VERSION 5.8 ;
BUSBITCHARS "[]" ;
DIVIDERCHAR "/" ;
UNITS
    DATABASE MICRONS 1000 ;
END UNITS

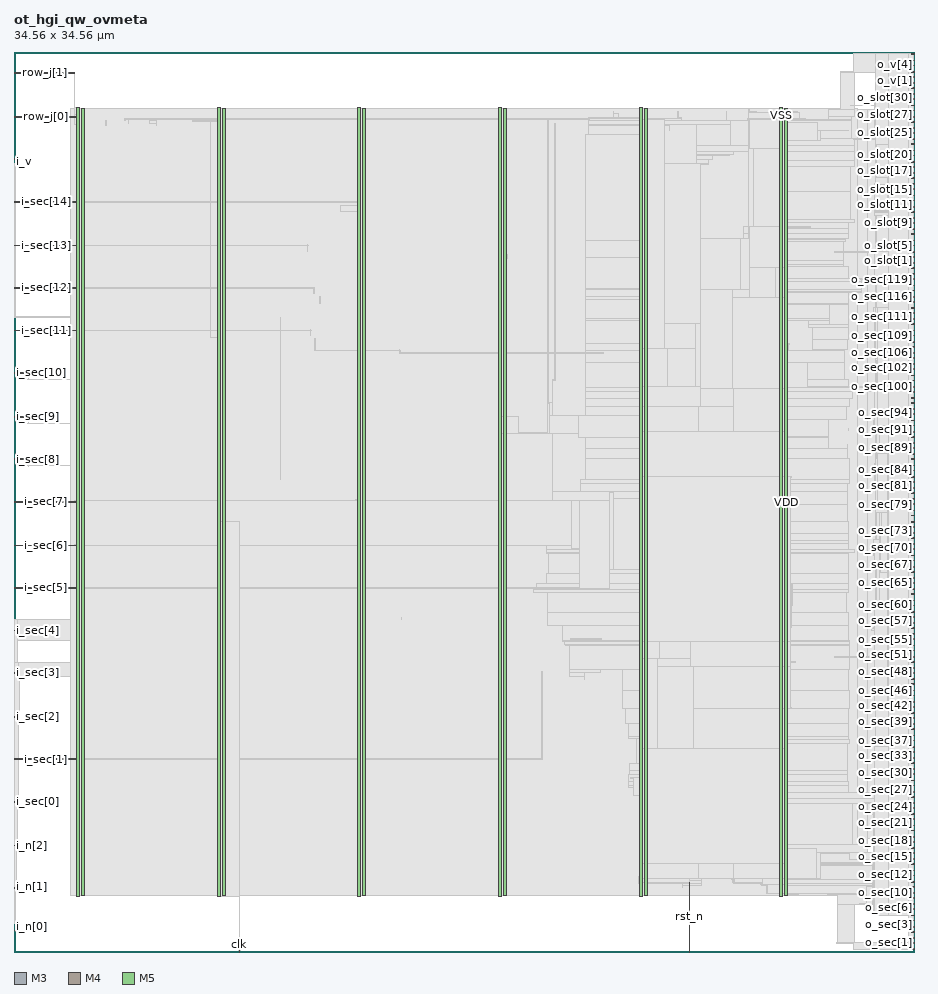
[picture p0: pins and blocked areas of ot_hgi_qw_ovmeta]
MACRO ot_hgi_qw_ovmeta
  FOREIGN ot_hgi_qw_ovmeta 0 0 ;
  CLASS BLOCK ;
  SIZE 34.56 BY 34.56 ;
  PIN clk
    DIRECTION INPUT ;
    USE SIGNAL ;
    PORT
      LAYER M3 ;
        RECT  8.64 0 8.658 0.038 ;
    END
    PORT
      LAYER M3 ;
        RECT  8.64 0.012 8.658 0.077 ;
    END
  END clk
  PIN i_n[0]
    DIRECTION INPUT ;
    USE SIGNAL ;
    PORT
      LAYER M4 ;
        RECT  0 0.816 0.084 0.84 ;
    END
    PORT
      LAYER M4 ;
        RECT  0.06 0.816 0.137 1.128 ;
    END
  END i_n[0]
  PIN i_n[1]
    DIRECTION INPUT ;
    USE SIGNAL ;
    PORT
      LAYER M4 ;
        RECT  0 2.448 0.084 2.472 ;
    END
    PORT
      LAYER M4 ;
        RECT  0.06 2.448 0.061 2.472 ;
    END
    PORT
      LAYER M4 ;
        RECT  0.061 2.448 0.173 2.568 ;
    END
  END i_n[1]
  PIN i_n[2]
    DIRECTION INPUT ;
    USE SIGNAL ;
    PORT
      LAYER M4 ;
        RECT  0 4.08 0.084 4.104 ;
    END
    PORT
      LAYER M4 ;
        RECT  0.06 4.08 0.137 4.104 ;
    END
  END i_n[2]
  PIN i_sec[0]
    DIRECTION INPUT ;
    USE SIGNAL ;
    PORT
      LAYER M4 ;
        RECT  0 5.76 0.084 5.784 ;
    END
    PORT
      LAYER M4 ;
        RECT  0.06 5.76 0.173 5.784 ;
    END
  END i_sec[0]
  PIN i_sec[10]
    DIRECTION INPUT ;
    USE SIGNAL ;
    PORT
      LAYER M4 ;
        RECT  0 22.224 0.084 22.248 ;
    END
    PORT
      LAYER M4 ;
        RECT  0.06 22.224 0.569 22.248 ;
    END
  END i_sec[10]
  PIN i_sec[11]
    DIRECTION INPUT ;
    USE SIGNAL ;
    PORT
      LAYER M4 ;
        RECT  0 23.856 0.084 23.88 ;
    END
    PORT
      LAYER M4 ;
        RECT  0.06 23.856 2.408 23.88 ;
    END
  END i_sec[11]
  PIN i_sec[12]
    DIRECTION INPUT ;
    USE SIGNAL ;
    PORT
      LAYER M4 ;
        RECT  0 25.488 0.084 25.512 ;
    END
    PORT
      LAYER M4 ;
        RECT  0.06 25.488 2.408 25.512 ;
    END
  END i_sec[12]
  PIN i_sec[13]
    DIRECTION INPUT ;
    USE SIGNAL ;
    PORT
      LAYER M4 ;
        RECT  0 27.12 0.084 27.144 ;
    END
    PORT
      LAYER M4 ;
        RECT  0.06 27.12 2.408 27.144 ;
    END
  END i_sec[13]
  PIN i_sec[14]
    DIRECTION INPUT ;
    USE SIGNAL ;
    PORT
      LAYER M4 ;
        RECT  0 28.8 0.084 28.824 ;
    END
    PORT
      LAYER M4 ;
        RECT  0.06 28.8 2.408 28.824 ;
    END
  END i_sec[14]
  PIN i_sec[1]
    DIRECTION INPUT ;
    USE SIGNAL ;
    PORT
      LAYER M4 ;
        RECT  0 7.392 0.084 7.416 ;
    END
    PORT
      LAYER M4 ;
        RECT  0.06 7.392 2.408 7.416 ;
    END
  END i_sec[1]
  PIN i_sec[2]
    DIRECTION INPUT ;
    USE SIGNAL ;
    PORT
      LAYER M4 ;
        RECT  0 9.024 0.084 9.048 ;
    END
    PORT
      LAYER M4 ;
        RECT  0.06 9.024 0.209 9.048 ;
    END
  END i_sec[2]
  PIN i_sec[3]
    DIRECTION INPUT ;
    USE SIGNAL ;
    PORT
      LAYER M4 ;
        RECT  0 10.704 0.084 10.728 ;
    END
    PORT
      LAYER M4 ;
        RECT  0.06 10.704 0.209 10.728 ;
    END
  END i_sec[3]
  PIN i_sec[4]
    DIRECTION INPUT ;
    USE SIGNAL ;
    PORT
      LAYER M4 ;
        RECT  0 12.336 0.084 12.36 ;
    END
    PORT
      LAYER M4 ;
        RECT  0.06 12.336 0.137 12.36 ;
    END
  END i_sec[4]
  PIN i_sec[5]
    DIRECTION INPUT ;
    USE SIGNAL ;
    PORT
      LAYER M4 ;
        RECT  0 13.968 0.084 13.992 ;
    END
    PORT
      LAYER M4 ;
        RECT  0.06 13.968 2.408 13.992 ;
    END
  END i_sec[5]
  PIN i_sec[6]
    DIRECTION INPUT ;
    USE SIGNAL ;
    PORT
      LAYER M4 ;
        RECT  0 15.6 0.084 15.624 ;
    END
    PORT
      LAYER M4 ;
        RECT  0.06 15.6 2.408 15.624 ;
    END
  END i_sec[6]
  PIN i_sec[7]
    DIRECTION INPUT ;
    USE SIGNAL ;
    PORT
      LAYER M4 ;
        RECT  0 17.28 0.084 17.304 ;
    END
    PORT
      LAYER M4 ;
        RECT  0.06 17.28 2.408 17.304 ;
    END
  END i_sec[7]
  PIN i_sec[8]
    DIRECTION INPUT ;
    USE SIGNAL ;
    PORT
      LAYER M4 ;
        RECT  0 18.912 0.084 18.936 ;
    END
    PORT
      LAYER M4 ;
        RECT  0.06 18.912 0.569 18.936 ;
    END
  END i_sec[8]
  PIN i_sec[9]
    DIRECTION INPUT ;
    USE SIGNAL ;
    PORT
      LAYER M4 ;
        RECT  0 20.544 0.084 20.568 ;
    END
    PORT
      LAYER M4 ;
        RECT  0.06 20.544 0.569 20.568 ;
    END
  END i_sec[9]
  PIN i_v
    DIRECTION INPUT ;
    USE SIGNAL ;
    PORT
      LAYER M4 ;
        RECT  0 30.432 0.084 30.456 ;
    END
    PORT
      LAYER M4 ;
        RECT  0.06 30.24 0.137 30.456 ;
    END
  END i_v
  PIN o_sec[0]
    DIRECTION OUTPUT ;
    USE SIGNAL ;
    PORT
      LAYER M4 ;
        RECT  34.476 0.096 34.56 0.12 ;
    END
  END o_sec[0]
  PIN o_sec[100]
    DIRECTION OUTPUT ;
    USE SIGNAL ;
    PORT
      LAYER M4 ;
        RECT  34.476 21.696 34.56 21.72 ;
    END
  END o_sec[100]
  PIN o_sec[101]
    DIRECTION OUTPUT ;
    USE SIGNAL ;
    PORT
      LAYER M4 ;
        RECT  34.476 21.936 34.56 21.96 ;
    END
  END o_sec[101]
  PIN o_sec[102]
    DIRECTION OUTPUT ;
    USE SIGNAL ;
    PORT
      LAYER M4 ;
        RECT  34.476 22.128 34.56 22.152 ;
    END
  END o_sec[102]
  PIN o_sec[103]
    DIRECTION OUTPUT ;
    USE SIGNAL ;
    PORT
      LAYER M4 ;
        RECT  34.476 22.368 34.56 22.392 ;
    END
  END o_sec[103]
  PIN o_sec[104]
    DIRECTION OUTPUT ;
    USE SIGNAL ;
    PORT
      LAYER M4 ;
        RECT  34.476 22.56 34.56 22.584 ;
    END
  END o_sec[104]
  PIN o_sec[105]
    DIRECTION OUTPUT ;
    USE SIGNAL ;
    PORT
      LAYER M4 ;
        RECT  34.476 22.8 34.56 22.824 ;
    END
  END o_sec[105]
  PIN o_sec[106]
    DIRECTION OUTPUT ;
    USE SIGNAL ;
    PORT
      LAYER M4 ;
        RECT  34.476 22.992 34.56 23.016 ;
    END
  END o_sec[106]
  PIN o_sec[107]
    DIRECTION OUTPUT ;
    USE SIGNAL ;
    PORT
      LAYER M4 ;
        RECT  34.476 23.232 34.56 23.256 ;
    END
  END o_sec[107]
  PIN o_sec[108]
    DIRECTION OUTPUT ;
    USE SIGNAL ;
    PORT
      LAYER M4 ;
        RECT  34.476 23.424 34.56 23.448 ;
    END
  END o_sec[108]
  PIN o_sec[109]
    DIRECTION OUTPUT ;
    USE SIGNAL ;
    PORT
      LAYER M4 ;
        RECT  34.476 23.664 34.56 23.688 ;
    END
  END o_sec[109]
  PIN o_sec[10]
    DIRECTION OUTPUT ;
    USE SIGNAL ;
    PORT
      LAYER M4 ;
        RECT  34.476 2.256 34.56 2.28 ;
    END
  END o_sec[10]
  PIN o_sec[110]
    DIRECTION OUTPUT ;
    USE SIGNAL ;
    PORT
      LAYER M4 ;
        RECT  34.476 23.856 34.56 23.88 ;
    END
  END o_sec[110]
  PIN o_sec[111]
    DIRECTION OUTPUT ;
    USE SIGNAL ;
    PORT
      LAYER M4 ;
        RECT  34.476 24.096 34.56 24.12 ;
    END
  END o_sec[111]
  PIN o_sec[112]
    DIRECTION OUTPUT ;
    USE SIGNAL ;
    PORT
      LAYER M4 ;
        RECT  34.476 24.288 34.56 24.312 ;
    END
  END o_sec[112]
  PIN o_sec[113]
    DIRECTION OUTPUT ;
    USE SIGNAL ;
    PORT
      LAYER M4 ;
        RECT  34.476 24.528 34.56 24.552 ;
    END
  END o_sec[113]
  PIN o_sec[114]
    DIRECTION OUTPUT ;
    USE SIGNAL ;
    PORT
      LAYER M4 ;
        RECT  34.476 24.72 34.56 24.744 ;
    END
  END o_sec[114]
  PIN o_sec[115]
    DIRECTION OUTPUT ;
    USE SIGNAL ;
    PORT
      LAYER M4 ;
        RECT  34.476 24.96 34.56 24.984 ;
    END
  END o_sec[115]
  PIN o_sec[116]
    DIRECTION OUTPUT ;
    USE SIGNAL ;
    PORT
      LAYER M4 ;
        RECT  34.476 25.152 34.56 25.176 ;
    END
  END o_sec[116]
  PIN o_sec[117]
    DIRECTION OUTPUT ;
    USE SIGNAL ;
    PORT
      LAYER M4 ;
        RECT  34.476 25.392 34.56 25.416 ;
    END
  END o_sec[117]
  PIN o_sec[118]
    DIRECTION OUTPUT ;
    USE SIGNAL ;
    PORT
      LAYER M4 ;
        RECT  34.476 25.584 34.56 25.608 ;
    END
  END o_sec[118]
  PIN o_sec[119]
    DIRECTION OUTPUT ;
    USE SIGNAL ;
    PORT
      LAYER M4 ;
        RECT  34.476 25.824 34.56 25.848 ;
    END
  END o_sec[119]
  PIN o_sec[11]
    DIRECTION OUTPUT ;
    USE SIGNAL ;
    PORT
      LAYER M4 ;
        RECT  34.476 2.496 34.56 2.52 ;
    END
  END o_sec[11]
  PIN o_sec[12]
    DIRECTION OUTPUT ;
    USE SIGNAL ;
    PORT
      LAYER M4 ;
        RECT  34.476 2.688 34.56 2.712 ;
    END
  END o_sec[12]
  PIN o_sec[13]
    DIRECTION OUTPUT ;
    USE SIGNAL ;
    PORT
      LAYER M4 ;
        RECT  34.476 2.928 34.56 2.952 ;
    END
  END o_sec[13]
  PIN o_sec[14]
    DIRECTION OUTPUT ;
    USE SIGNAL ;
    PORT
      LAYER M4 ;
        RECT  34.476 3.12 34.56 3.144 ;
    END
  END o_sec[14]
  PIN o_sec[15]
    DIRECTION OUTPUT ;
    USE SIGNAL ;
    PORT
      LAYER M4 ;
        RECT  34.476 3.36 34.56 3.384 ;
    END
  END o_sec[15]
  PIN o_sec[16]
    DIRECTION OUTPUT ;
    USE SIGNAL ;
    PORT
      LAYER M4 ;
        RECT  34.476 3.552 34.56 3.576 ;
    END
  END o_sec[16]
  PIN o_sec[17]
    DIRECTION OUTPUT ;
    USE SIGNAL ;
    PORT
      LAYER M4 ;
        RECT  34.476 3.792 34.56 3.816 ;
    END
  END o_sec[17]
  PIN o_sec[18]
    DIRECTION OUTPUT ;
    USE SIGNAL ;
    PORT
      LAYER M4 ;
        RECT  34.476 3.984 34.56 4.008 ;
    END
  END o_sec[18]
  PIN o_sec[19]
    DIRECTION OUTPUT ;
    USE SIGNAL ;
    PORT
      LAYER M4 ;
        RECT  34.476 4.224 34.56 4.248 ;
    END
  END o_sec[19]
  PIN o_sec[1]
    DIRECTION OUTPUT ;
    USE SIGNAL ;
    PORT
      LAYER M4 ;
        RECT  34.476 0.336 34.56 0.36 ;
    END
  END o_sec[1]
  PIN o_sec[20]
    DIRECTION OUTPUT ;
    USE SIGNAL ;
    PORT
      LAYER M4 ;
        RECT  34.476 4.416 34.56 4.44 ;
    END
  END o_sec[20]
  PIN o_sec[21]
    DIRECTION OUTPUT ;
    USE SIGNAL ;
    PORT
      LAYER M4 ;
        RECT  34.476 4.656 34.56 4.68 ;
    END
  END o_sec[21]
  PIN o_sec[22]
    DIRECTION OUTPUT ;
    USE SIGNAL ;
    PORT
      LAYER M4 ;
        RECT  34.476 4.848 34.56 4.872 ;
    END
  END o_sec[22]
  PIN o_sec[23]
    DIRECTION OUTPUT ;
    USE SIGNAL ;
    PORT
      LAYER M4 ;
        RECT  34.476 5.088 34.56 5.112 ;
    END
  END o_sec[23]
  PIN o_sec[24]
    DIRECTION OUTPUT ;
    USE SIGNAL ;
    PORT
      LAYER M4 ;
        RECT  34.476 5.28 34.56 5.304 ;
    END
  END o_sec[24]
  PIN o_sec[25]
    DIRECTION OUTPUT ;
    USE SIGNAL ;
    PORT
      LAYER M4 ;
        RECT  34.476 5.52 34.56 5.544 ;
    END
  END o_sec[25]
  PIN o_sec[26]
    DIRECTION OUTPUT ;
    USE SIGNAL ;
    PORT
      LAYER M4 ;
        RECT  34.476 5.712 34.56 5.736 ;
    END
  END o_sec[26]
  PIN o_sec[27]
    DIRECTION OUTPUT ;
    USE SIGNAL ;
    PORT
      LAYER M4 ;
        RECT  34.476 5.952 34.56 5.976 ;
    END
  END o_sec[27]
  PIN o_sec[28]
    DIRECTION OUTPUT ;
    USE SIGNAL ;
    PORT
      LAYER M4 ;
        RECT  34.476 6.144 34.56 6.168 ;
    END
  END o_sec[28]
  PIN o_sec[29]
    DIRECTION OUTPUT ;
    USE SIGNAL ;
    PORT
      LAYER M4 ;
        RECT  34.476 6.384 34.56 6.408 ;
    END
  END o_sec[29]
  PIN o_sec[2]
    DIRECTION OUTPUT ;
    USE SIGNAL ;
    PORT
      LAYER M4 ;
        RECT  34.476 0.528 34.56 0.552 ;
    END
  END o_sec[2]
  PIN o_sec[30]
    DIRECTION OUTPUT ;
    USE SIGNAL ;
    PORT
      LAYER M4 ;
        RECT  34.476 6.576 34.56 6.6 ;
    END
  END o_sec[30]
  PIN o_sec[31]
    DIRECTION OUTPUT ;
    USE SIGNAL ;
    PORT
      LAYER M4 ;
        RECT  34.476 6.816 34.56 6.84 ;
    END
  END o_sec[31]
  PIN o_sec[32]
    DIRECTION OUTPUT ;
    USE SIGNAL ;
    PORT
      LAYER M4 ;
        RECT  34.476 7.008 34.56 7.032 ;
    END
  END o_sec[32]
  PIN o_sec[33]
    DIRECTION OUTPUT ;
    USE SIGNAL ;
    PORT
      LAYER M4 ;
        RECT  34.476 7.248 34.56 7.272 ;
    END
  END o_sec[33]
  PIN o_sec[34]
    DIRECTION OUTPUT ;
    USE SIGNAL ;
    PORT
      LAYER M4 ;
        RECT  34.476 7.44 34.56 7.464 ;
    END
  END o_sec[34]
  PIN o_sec[35]
    DIRECTION OUTPUT ;
    USE SIGNAL ;
    PORT
      LAYER M4 ;
        RECT  34.476 7.68 34.56 7.704 ;
    END
  END o_sec[35]
  PIN o_sec[36]
    DIRECTION OUTPUT ;
    USE SIGNAL ;
    PORT
      LAYER M4 ;
        RECT  34.476 7.872 34.56 7.896 ;
    END
  END o_sec[36]
  PIN o_sec[37]
    DIRECTION OUTPUT ;
    USE SIGNAL ;
    PORT
      LAYER M4 ;
        RECT  34.476 8.112 34.56 8.136 ;
    END
  END o_sec[37]
  PIN o_sec[38]
    DIRECTION OUTPUT ;
    USE SIGNAL ;
    PORT
      LAYER M4 ;
        RECT  34.476 8.304 34.56 8.328 ;
    END
  END o_sec[38]
  PIN o_sec[39]
    DIRECTION OUTPUT ;
    USE SIGNAL ;
    PORT
      LAYER M4 ;
        RECT  34.476 8.544 34.56 8.568 ;
    END
  END o_sec[39]
  PIN o_sec[3]
    DIRECTION OUTPUT ;
    USE SIGNAL ;
    PORT
      LAYER M4 ;
        RECT  34.476 0.768 34.56 0.792 ;
    END
  END o_sec[3]
  PIN o_sec[40]
    DIRECTION OUTPUT ;
    USE SIGNAL ;
    PORT
      LAYER M4 ;
        RECT  34.476 8.736 34.56 8.76 ;
    END
  END o_sec[40]
  PIN o_sec[41]
    DIRECTION OUTPUT ;
    USE SIGNAL ;
    PORT
      LAYER M4 ;
        RECT  34.476 8.976 34.56 9 ;
    END
  END o_sec[41]
  PIN o_sec[42]
    DIRECTION OUTPUT ;
    USE SIGNAL ;
    PORT
      LAYER M4 ;
        RECT  34.476 9.168 34.56 9.192 ;
    END
  END o_sec[42]
  PIN o_sec[43]
    DIRECTION OUTPUT ;
    USE SIGNAL ;
    PORT
      LAYER M4 ;
        RECT  34.476 9.408 34.56 9.432 ;
    END
  END o_sec[43]
  PIN o_sec[44]
    DIRECTION OUTPUT ;
    USE SIGNAL ;
    PORT
      LAYER M4 ;
        RECT  34.476 9.6 34.56 9.624 ;
    END
  END o_sec[44]
  PIN o_sec[45]
    DIRECTION OUTPUT ;
    USE SIGNAL ;
    PORT
      LAYER M4 ;
        RECT  34.476 9.84 34.56 9.864 ;
    END
  END o_sec[45]
  PIN o_sec[46]
    DIRECTION OUTPUT ;
    USE SIGNAL ;
    PORT
      LAYER M4 ;
        RECT  34.476 10.032 34.56 10.056 ;
    END
  END o_sec[46]
  PIN o_sec[47]
    DIRECTION OUTPUT ;
    USE SIGNAL ;
    PORT
      LAYER M4 ;
        RECT  34.476 10.272 34.56 10.296 ;
    END
  END o_sec[47]
  PIN o_sec[48]
    DIRECTION OUTPUT ;
    USE SIGNAL ;
    PORT
      LAYER M4 ;
        RECT  34.476 10.464 34.56 10.488 ;
    END
  END o_sec[48]
  PIN o_sec[49]
    DIRECTION OUTPUT ;
    USE SIGNAL ;
    PORT
      LAYER M4 ;
        RECT  34.476 10.704 34.56 10.728 ;
    END
  END o_sec[49]
  PIN o_sec[4]
    DIRECTION OUTPUT ;
    USE SIGNAL ;
    PORT
      LAYER M4 ;
        RECT  34.476 0.96 34.56 0.984 ;
    END
  END o_sec[4]
  PIN o_sec[50]
    DIRECTION OUTPUT ;
    USE SIGNAL ;
    PORT
      LAYER M4 ;
        RECT  34.476 10.896 34.56 10.92 ;
    END
  END o_sec[50]
  PIN o_sec[51]
    DIRECTION OUTPUT ;
    USE SIGNAL ;
    PORT
      LAYER M4 ;
        RECT  34.476 11.136 34.56 11.16 ;
    END
  END o_sec[51]
  PIN o_sec[52]
    DIRECTION OUTPUT ;
    USE SIGNAL ;
    PORT
      LAYER M4 ;
        RECT  34.476 11.328 34.56 11.352 ;
    END
  END o_sec[52]
  PIN o_sec[53]
    DIRECTION OUTPUT ;
    USE SIGNAL ;
    PORT
      LAYER M4 ;
        RECT  34.476 11.568 34.56 11.592 ;
    END
  END o_sec[53]
  PIN o_sec[54]
    DIRECTION OUTPUT ;
    USE SIGNAL ;
    PORT
      LAYER M4 ;
        RECT  34.476 11.76 34.56 11.784 ;
    END
  END o_sec[54]
  PIN o_sec[55]
    DIRECTION OUTPUT ;
    USE SIGNAL ;
    PORT
      LAYER M4 ;
        RECT  34.476 12 34.56 12.024 ;
    END
  END o_sec[55]
  PIN o_sec[56]
    DIRECTION OUTPUT ;
    USE SIGNAL ;
    PORT
      LAYER M4 ;
        RECT  34.476 12.192 34.56 12.216 ;
    END
  END o_sec[56]
  PIN o_sec[57]
    DIRECTION OUTPUT ;
    USE SIGNAL ;
    PORT
      LAYER M4 ;
        RECT  34.476 12.432 34.56 12.456 ;
    END
  END o_sec[57]
  PIN o_sec[58]
    DIRECTION OUTPUT ;
    USE SIGNAL ;
    PORT
      LAYER M4 ;
        RECT  34.476 12.624 34.56 12.648 ;
    END
  END o_sec[58]
  PIN o_sec[59]
    DIRECTION OUTPUT ;
    USE SIGNAL ;
    PORT
      LAYER M4 ;
        RECT  34.476 12.864 34.56 12.888 ;
    END
  END o_sec[59]
  PIN o_sec[5]
    DIRECTION OUTPUT ;
    USE SIGNAL ;
    PORT
      LAYER M4 ;
        RECT  34.476 1.2 34.56 1.224 ;
    END
  END o_sec[5]
  PIN o_sec[60]
    DIRECTION OUTPUT ;
    USE SIGNAL ;
    PORT
      LAYER M4 ;
        RECT  34.476 13.056 34.56 13.08 ;
    END
  END o_sec[60]
  PIN o_sec[61]
    DIRECTION OUTPUT ;
    USE SIGNAL ;
    PORT
      LAYER M4 ;
        RECT  34.476 13.296 34.56 13.32 ;
    END
  END o_sec[61]
  PIN o_sec[62]
    DIRECTION OUTPUT ;
    USE SIGNAL ;
    PORT
      LAYER M4 ;
        RECT  34.476 13.488 34.56 13.512 ;
    END
  END o_sec[62]
  PIN o_sec[63]
    DIRECTION OUTPUT ;
    USE SIGNAL ;
    PORT
      LAYER M4 ;
        RECT  34.476 13.728 34.56 13.752 ;
    END
  END o_sec[63]
  PIN o_sec[64]
    DIRECTION OUTPUT ;
    USE SIGNAL ;
    PORT
      LAYER M4 ;
        RECT  34.476 13.92 34.56 13.944 ;
    END
  END o_sec[64]
  PIN o_sec[65]
    DIRECTION OUTPUT ;
    USE SIGNAL ;
    PORT
      LAYER M4 ;
        RECT  34.476 14.16 34.56 14.184 ;
    END
  END o_sec[65]
  PIN o_sec[66]
    DIRECTION OUTPUT ;
    USE SIGNAL ;
    PORT
      LAYER M4 ;
        RECT  34.476 14.352 34.56 14.376 ;
    END
  END o_sec[66]
  PIN o_sec[67]
    DIRECTION OUTPUT ;
    USE SIGNAL ;
    PORT
      LAYER M4 ;
        RECT  34.476 14.592 34.56 14.616 ;
    END
  END o_sec[67]
  PIN o_sec[68]
    DIRECTION OUTPUT ;
    USE SIGNAL ;
    PORT
      LAYER M4 ;
        RECT  34.476 14.784 34.56 14.808 ;
    END
  END o_sec[68]
  PIN o_sec[69]
    DIRECTION OUTPUT ;
    USE SIGNAL ;
    PORT
      LAYER M4 ;
        RECT  34.476 15.024 34.56 15.048 ;
    END
  END o_sec[69]
  PIN o_sec[6]
    DIRECTION OUTPUT ;
    USE SIGNAL ;
    PORT
      LAYER M4 ;
        RECT  34.476 1.392 34.56 1.416 ;
    END
  END o_sec[6]
  PIN o_sec[70]
    DIRECTION OUTPUT ;
    USE SIGNAL ;
    PORT
      LAYER M4 ;
        RECT  34.476 15.216 34.56 15.24 ;
    END
  END o_sec[70]
  PIN o_sec[71]
    DIRECTION OUTPUT ;
    USE SIGNAL ;
    PORT
      LAYER M4 ;
        RECT  34.476 15.456 34.56 15.48 ;
    END
  END o_sec[71]
  PIN o_sec[72]
    DIRECTION OUTPUT ;
    USE SIGNAL ;
    PORT
      LAYER M4 ;
        RECT  34.476 15.648 34.56 15.672 ;
    END
  END o_sec[72]
  PIN o_sec[73]
    DIRECTION OUTPUT ;
    USE SIGNAL ;
    PORT
      LAYER M4 ;
        RECT  34.476 15.888 34.56 15.912 ;
    END
  END o_sec[73]
  PIN o_sec[74]
    DIRECTION OUTPUT ;
    USE SIGNAL ;
    PORT
      LAYER M4 ;
        RECT  34.476 16.08 34.56 16.104 ;
    END
  END o_sec[74]
  PIN o_sec[75]
    DIRECTION OUTPUT ;
    USE SIGNAL ;
    PORT
      LAYER M4 ;
        RECT  34.476 16.32 34.56 16.344 ;
    END
  END o_sec[75]
  PIN o_sec[76]
    DIRECTION OUTPUT ;
    USE SIGNAL ;
    PORT
      LAYER M4 ;
        RECT  34.476 16.512 34.56 16.536 ;
    END
  END o_sec[76]
  PIN o_sec[77]
    DIRECTION OUTPUT ;
    USE SIGNAL ;
    PORT
      LAYER M4 ;
        RECT  34.476 16.752 34.56 16.776 ;
    END
  END o_sec[77]
  PIN o_sec[78]
    DIRECTION OUTPUT ;
    USE SIGNAL ;
    PORT
      LAYER M4 ;
        RECT  34.476 16.944 34.56 16.968 ;
    END
  END o_sec[78]
  PIN o_sec[79]
    DIRECTION OUTPUT ;
    USE SIGNAL ;
    PORT
      LAYER M4 ;
        RECT  34.476 17.184 34.56 17.208 ;
    END
  END o_sec[79]
  PIN o_sec[7]
    DIRECTION OUTPUT ;
    USE SIGNAL ;
    PORT
      LAYER M4 ;
        RECT  34.476 1.632 34.56 1.656 ;
    END
  END o_sec[7]
  PIN o_sec[80]
    DIRECTION OUTPUT ;
    USE SIGNAL ;
    PORT
      LAYER M4 ;
        RECT  34.476 17.376 34.56 17.4 ;
    END
  END o_sec[80]
  PIN o_sec[81]
    DIRECTION OUTPUT ;
    USE SIGNAL ;
    PORT
      LAYER M4 ;
        RECT  34.476 17.616 34.56 17.64 ;
    END
  END o_sec[81]
  PIN o_sec[82]
    DIRECTION OUTPUT ;
    USE SIGNAL ;
    PORT
      LAYER M4 ;
        RECT  34.476 17.808 34.56 17.832 ;
    END
  END o_sec[82]
  PIN o_sec[83]
    DIRECTION OUTPUT ;
    USE SIGNAL ;
    PORT
      LAYER M4 ;
        RECT  34.476 18.048 34.56 18.072 ;
    END
  END o_sec[83]
  PIN o_sec[84]
    DIRECTION OUTPUT ;
    USE SIGNAL ;
    PORT
      LAYER M4 ;
        RECT  34.476 18.24 34.56 18.264 ;
    END
  END o_sec[84]
  PIN o_sec[85]
    DIRECTION OUTPUT ;
    USE SIGNAL ;
    PORT
      LAYER M4 ;
        RECT  34.476 18.48 34.56 18.504 ;
    END
  END o_sec[85]
  PIN o_sec[86]
    DIRECTION OUTPUT ;
    USE SIGNAL ;
    PORT
      LAYER M4 ;
        RECT  34.476 18.672 34.56 18.696 ;
    END
  END o_sec[86]
  PIN o_sec[87]
    DIRECTION OUTPUT ;
    USE SIGNAL ;
    PORT
      LAYER M4 ;
        RECT  34.476 18.912 34.56 18.936 ;
    END
  END o_sec[87]
  PIN o_sec[88]
    DIRECTION OUTPUT ;
    USE SIGNAL ;
    PORT
      LAYER M4 ;
        RECT  34.476 19.104 34.56 19.128 ;
    END
  END o_sec[88]
  PIN o_sec[89]
    DIRECTION OUTPUT ;
    USE SIGNAL ;
    PORT
      LAYER M4 ;
        RECT  34.476 19.344 34.56 19.368 ;
    END
  END o_sec[89]
  PIN o_sec[8]
    DIRECTION OUTPUT ;
    USE SIGNAL ;
    PORT
      LAYER M4 ;
        RECT  34.476 1.824 34.56 1.848 ;
    END
  END o_sec[8]
  PIN o_sec[90]
    DIRECTION OUTPUT ;
    USE SIGNAL ;
    PORT
      LAYER M4 ;
        RECT  34.476 19.536 34.56 19.56 ;
    END
  END o_sec[90]
  PIN o_sec[91]
    DIRECTION OUTPUT ;
    USE SIGNAL ;
    PORT
      LAYER M4 ;
        RECT  34.476 19.776 34.56 19.8 ;
    END
  END o_sec[91]
  PIN o_sec[92]
    DIRECTION OUTPUT ;
    USE SIGNAL ;
    PORT
      LAYER M4 ;
        RECT  34.476 19.968 34.56 19.992 ;
    END
  END o_sec[92]
  PIN o_sec[93]
    DIRECTION OUTPUT ;
    USE SIGNAL ;
    PORT
      LAYER M4 ;
        RECT  34.476 20.208 34.56 20.232 ;
    END
  END o_sec[93]
  PIN o_sec[94]
    DIRECTION OUTPUT ;
    USE SIGNAL ;
    PORT
      LAYER M4 ;
        RECT  34.476 20.4 34.56 20.424 ;
    END
  END o_sec[94]
  PIN o_sec[95]
    DIRECTION OUTPUT ;
    USE SIGNAL ;
    PORT
      LAYER M4 ;
        RECT  34.476 20.64 34.56 20.664 ;
    END
  END o_sec[95]
  PIN o_sec[96]
    DIRECTION OUTPUT ;
    USE SIGNAL ;
    PORT
      LAYER M4 ;
        RECT  34.476 20.832 34.56 20.856 ;
    END
  END o_sec[96]
  PIN o_sec[97]
    DIRECTION OUTPUT ;
    USE SIGNAL ;
    PORT
      LAYER M4 ;
        RECT  34.476 21.072 34.56 21.096 ;
    END
  END o_sec[97]
  PIN o_sec[98]
    DIRECTION OUTPUT ;
    USE SIGNAL ;
    PORT
      LAYER M4 ;
        RECT  34.476 21.264 34.56 21.288 ;
    END
  END o_sec[98]
  PIN o_sec[99]
    DIRECTION OUTPUT ;
    USE SIGNAL ;
    PORT
      LAYER M4 ;
        RECT  34.476 21.504 34.56 21.528 ;
    END
  END o_sec[99]
  PIN o_sec[9]
    DIRECTION OUTPUT ;
    USE SIGNAL ;
    PORT
      LAYER M4 ;
        RECT  34.476 2.064 34.56 2.088 ;
    END
  END o_sec[9]
  PIN o_slot[0]
    DIRECTION OUTPUT ;
    USE SIGNAL ;
    PORT
      LAYER M4 ;
        RECT  34.476 26.016 34.56 26.04 ;
    END
  END o_slot[0]
  PIN o_slot[10]
    DIRECTION OUTPUT ;
    USE SIGNAL ;
    PORT
      LAYER M4 ;
        RECT  34.476 28.176 34.56 28.2 ;
    END
  END o_slot[10]
  PIN o_slot[11]
    DIRECTION OUTPUT ;
    USE SIGNAL ;
    PORT
      LAYER M4 ;
        RECT  34.476 28.416 34.56 28.44 ;
    END
  END o_slot[11]
  PIN o_slot[12]
    DIRECTION OUTPUT ;
    USE SIGNAL ;
    PORT
      LAYER M4 ;
        RECT  34.476 28.608 34.56 28.632 ;
    END
  END o_slot[12]
  PIN o_slot[13]
    DIRECTION OUTPUT ;
    USE SIGNAL ;
    PORT
      LAYER M4 ;
        RECT  34.476 28.848 34.56 28.872 ;
    END
  END o_slot[13]
  PIN o_slot[14]
    DIRECTION OUTPUT ;
    USE SIGNAL ;
    PORT
      LAYER M4 ;
        RECT  34.476 29.04 34.56 29.064 ;
    END
  END o_slot[14]
  PIN o_slot[15]
    DIRECTION OUTPUT ;
    USE SIGNAL ;
    PORT
      LAYER M4 ;
        RECT  34.476 29.28 34.56 29.304 ;
    END
  END o_slot[15]
  PIN o_slot[16]
    DIRECTION OUTPUT ;
    USE SIGNAL ;
    PORT
      LAYER M4 ;
        RECT  34.476 29.472 34.56 29.496 ;
    END
  END o_slot[16]
  PIN o_slot[17]
    DIRECTION OUTPUT ;
    USE SIGNAL ;
    PORT
      LAYER M4 ;
        RECT  34.476 29.712 34.56 29.736 ;
    END
  END o_slot[17]
  PIN o_slot[18]
    DIRECTION OUTPUT ;
    USE SIGNAL ;
    PORT
      LAYER M4 ;
        RECT  34.476 29.904 34.56 29.928 ;
    END
  END o_slot[18]
  PIN o_slot[19]
    DIRECTION OUTPUT ;
    USE SIGNAL ;
    PORT
      LAYER M4 ;
        RECT  34.476 30.144 34.56 30.168 ;
    END
  END o_slot[19]
  PIN o_slot[1]
    DIRECTION OUTPUT ;
    USE SIGNAL ;
    PORT
      LAYER M4 ;
        RECT  34.476 26.256 34.56 26.28 ;
    END
  END o_slot[1]
  PIN o_slot[20]
    DIRECTION OUTPUT ;
    USE SIGNAL ;
    PORT
      LAYER M4 ;
        RECT  34.476 30.336 34.56 30.36 ;
    END
  END o_slot[20]
  PIN o_slot[21]
    DIRECTION OUTPUT ;
    USE SIGNAL ;
    PORT
      LAYER M4 ;
        RECT  34.476 30.576 34.56 30.6 ;
    END
  END o_slot[21]
  PIN o_slot[22]
    DIRECTION OUTPUT ;
    USE SIGNAL ;
    PORT
      LAYER M4 ;
        RECT  34.476 30.768 34.56 30.792 ;
    END
  END o_slot[22]
  PIN o_slot[23]
    DIRECTION OUTPUT ;
    USE SIGNAL ;
    PORT
      LAYER M4 ;
        RECT  34.476 31.008 34.56 31.032 ;
    END
  END o_slot[23]
  PIN o_slot[24]
    DIRECTION OUTPUT ;
    USE SIGNAL ;
    PORT
      LAYER M4 ;
        RECT  34.476 31.2 34.56 31.224 ;
    END
  END o_slot[24]
  PIN o_slot[25]
    DIRECTION OUTPUT ;
    USE SIGNAL ;
    PORT
      LAYER M4 ;
        RECT  34.476 31.44 34.56 31.464 ;
    END
  END o_slot[25]
  PIN o_slot[26]
    DIRECTION OUTPUT ;
    USE SIGNAL ;
    PORT
      LAYER M4 ;
        RECT  34.476 31.632 34.56 31.656 ;
    END
  END o_slot[26]
  PIN o_slot[27]
    DIRECTION OUTPUT ;
    USE SIGNAL ;
    PORT
      LAYER M4 ;
        RECT  34.476 31.872 34.56 31.896 ;
    END
  END o_slot[27]
  PIN o_slot[28]
    DIRECTION OUTPUT ;
    USE SIGNAL ;
    PORT
      LAYER M4 ;
        RECT  34.476 32.064 34.56 32.088 ;
    END
  END o_slot[28]
  PIN o_slot[29]
    DIRECTION OUTPUT ;
    USE SIGNAL ;
    PORT
      LAYER M4 ;
        RECT  34.476 32.304 34.56 32.328 ;
    END
  END o_slot[29]
  PIN o_slot[2]
    DIRECTION OUTPUT ;
    USE SIGNAL ;
    PORT
      LAYER M4 ;
        RECT  34.476 26.448 34.56 26.472 ;
    END
  END o_slot[2]
  PIN o_slot[30]
    DIRECTION OUTPUT ;
    USE SIGNAL ;
    PORT
      LAYER M4 ;
        RECT  34.476 32.496 34.56 32.52 ;
    END
  END o_slot[30]
  PIN o_slot[31]
    DIRECTION OUTPUT ;
    USE SIGNAL ;
    PORT
      LAYER M4 ;
        RECT  34.476 32.736 34.56 32.76 ;
    END
  END o_slot[31]
  PIN o_slot[3]
    DIRECTION OUTPUT ;
    USE SIGNAL ;
    PORT
      LAYER M4 ;
        RECT  34.476 26.688 34.56 26.712 ;
    END
  END o_slot[3]
  PIN o_slot[4]
    DIRECTION OUTPUT ;
    USE SIGNAL ;
    PORT
      LAYER M4 ;
        RECT  34.476 26.88 34.56 26.904 ;
    END
  END o_slot[4]
  PIN o_slot[5]
    DIRECTION OUTPUT ;
    USE SIGNAL ;
    PORT
      LAYER M4 ;
        RECT  34.476 27.12 34.56 27.144 ;
    END
  END o_slot[5]
  PIN o_slot[6]
    DIRECTION OUTPUT ;
    USE SIGNAL ;
    PORT
      LAYER M4 ;
        RECT  34.476 27.312 34.56 27.336 ;
    END
  END o_slot[6]
  PIN o_slot[7]
    DIRECTION OUTPUT ;
    USE SIGNAL ;
    PORT
      LAYER M4 ;
        RECT  34.476 27.552 34.56 27.576 ;
    END
  END o_slot[7]
  PIN o_slot[8]
    DIRECTION OUTPUT ;
    USE SIGNAL ;
    PORT
      LAYER M4 ;
        RECT  34.476 27.744 34.56 27.768 ;
    END
  END o_slot[8]
  PIN o_slot[9]
    DIRECTION OUTPUT ;
    USE SIGNAL ;
    PORT
      LAYER M4 ;
        RECT  34.476 27.984 34.56 28.008 ;
    END
  END o_slot[9]
  PIN o_v[0]
    DIRECTION OUTPUT ;
    USE SIGNAL ;
    PORT
      LAYER M4 ;
        RECT  34.476 32.928 34.56 32.952 ;
    END
  END o_v[0]
  PIN o_v[1]
    DIRECTION OUTPUT ;
    USE SIGNAL ;
    PORT
      LAYER M4 ;
        RECT  34.476 33.168 34.56 33.192 ;
    END
  END o_v[1]
  PIN o_v[2]
    DIRECTION OUTPUT ;
    USE SIGNAL ;
    PORT
      LAYER M4 ;
        RECT  34.476 33.36 34.56 33.384 ;
    END
  END o_v[2]
  PIN o_v[3]
    DIRECTION OUTPUT ;
    USE SIGNAL ;
    PORT
      LAYER M4 ;
        RECT  34.476 33.6 34.56 33.624 ;
    END
  END o_v[3]
  PIN o_v[4]
    DIRECTION OUTPUT ;
    USE SIGNAL ;
    PORT
      LAYER M4 ;
        RECT  34.476 33.792 34.56 33.816 ;
    END
  END o_v[4]
  PIN o_v[5]
    DIRECTION OUTPUT ;
    USE SIGNAL ;
    PORT
      LAYER M4 ;
        RECT  34.476 34.032 34.56 34.056 ;
    END
  END o_v[5]
  PIN o_v[6]
    DIRECTION OUTPUT ;
    USE SIGNAL ;
    PORT
      LAYER M4 ;
        RECT  34.476 34.224 34.56 34.248 ;
    END
  END o_v[6]
  PIN o_v[7]
    DIRECTION OUTPUT ;
    USE SIGNAL ;
    PORT
      LAYER M4 ;
        RECT  34.476 34.464 34.56 34.488 ;
    END
  END o_v[7]
  PIN row_j[0]
    DIRECTION INPUT ;
    USE SIGNAL ;
    PORT
      LAYER M4 ;
        RECT  0 32.064 0.084 32.088 ;
    END
    PORT
      LAYER M4 ;
        RECT  0.06 32.064 2.408 32.088 ;
    END
  END row_j[0]
  PIN row_j[1]
    DIRECTION INPUT ;
    USE SIGNAL ;
    PORT
      LAYER M4 ;
        RECT  0 33.744 0.084 33.768 ;
    END
    PORT
      LAYER M4 ;
        RECT  0.06 33.744 2.333 33.768 ;
    END
  END row_j[1]
  PIN rst_n
    DIRECTION INPUT ;
    USE SIGNAL ;
    PORT
      LAYER M5 ;
        RECT  25.92 0 25.944 0.084 ;
    END
    PORT
      LAYER M5 ;
        RECT  25.92 0.016 25.944 2.677 ;
    END
  END rst_n
  PIN VDD
    DIRECTION INOUT ;
    USE POWER ;
    PORT
      LAYER M5 ;
        RECT  29.592 2.151 29.712 32.409 ;
        RECT  24.192 2.151 24.312 32.409 ;
        RECT  18.792 2.151 18.912 32.409 ;
        RECT  13.392 2.151 13.512 32.409 ;
        RECT  7.992 2.151 8.112 32.409 ;
        RECT  2.592 2.151 2.712 32.409 ;
    END
  END VDD
  PIN VSS
    DIRECTION INOUT ;
    USE GROUND ;
    PORT
      LAYER M5 ;
        RECT  29.4 2.137 29.52 32.423 ;
        RECT  24 2.137 24.12 32.423 ;
        RECT  18.6 2.137 18.72 32.423 ;
        RECT  13.2 2.137 13.32 32.423 ;
        RECT  7.8 2.137 7.92 32.423 ;
        RECT  2.4 2.137 2.52 32.423 ;
    END
  END VSS
  # OT_OBS_CLOSED layer=M5 d_um=1.536 added=16
  OBS
    LAYER RVTN ;
     RECT  2.16 2.16 32.4 2.295 ;
     RECT  2.16 2.565 32.4 2.835 ;
     RECT  2.16 3.105 32.4 3.375 ;
     RECT  2.16 3.645 32.4 3.915 ;
     RECT  2.16 4.185 32.4 4.455 ;
     RECT  2.16 4.725 32.4 4.995 ;
     RECT  2.16 5.265 32.4 5.535 ;
     RECT  2.16 5.805 32.4 6.075 ;
     RECT  2.16 6.345 32.4 6.615 ;
     RECT  2.16 6.885 32.4 7.155 ;
     RECT  2.16 7.425 32.4 7.695 ;
     RECT  2.16 7.965 32.4 8.235 ;
     RECT  2.16 8.505 32.4 8.775 ;
     RECT  2.16 9.045 32.4 9.315 ;
     RECT  2.16 9.585 32.4 9.855 ;
     RECT  2.16 10.125 32.4 10.395 ;
     RECT  2.16 10.665 32.4 10.935 ;
     RECT  2.16 11.205 32.4 11.475 ;
     RECT  2.16 11.745 32.4 12.015 ;
     RECT  2.16 12.285 32.4 12.555 ;
     RECT  2.16 12.825 32.4 13.095 ;
     RECT  2.16 13.365 32.4 13.635 ;
     RECT  2.16 13.905 32.4 14.175 ;
     RECT  2.16 14.445 32.4 14.715 ;
     RECT  2.16 14.985 32.4 15.255 ;
     RECT  2.16 15.525 32.4 15.795 ;
     RECT  2.16 16.065 32.4 16.335 ;
     RECT  2.16 16.605 32.4 16.875 ;
     RECT  2.16 17.145 32.4 17.415 ;
     RECT  2.16 17.685 32.4 17.955 ;
     RECT  2.16 18.225 32.4 18.495 ;
     RECT  2.16 18.765 32.4 19.035 ;
     RECT  2.16 19.305 32.4 19.575 ;
     RECT  2.16 19.845 32.4 20.115 ;
     RECT  2.16 20.385 32.4 20.655 ;
     RECT  2.16 20.925 32.4 21.195 ;
     RECT  2.16 21.465 32.4 21.735 ;
     RECT  2.16 22.005 32.4 22.275 ;
     RECT  2.16 22.545 32.4 22.815 ;
     RECT  2.16 23.085 32.4 23.355 ;
     RECT  2.16 23.625 32.4 23.895 ;
     RECT  2.16 24.165 32.4 24.435 ;
     RECT  2.16 24.705 32.4 24.975 ;
     RECT  2.16 25.245 32.4 25.515 ;
     RECT  2.16 25.785 32.4 26.055 ;
     RECT  2.16 26.325 32.4 26.595 ;
     RECT  2.16 26.865 32.4 27.135 ;
     RECT  2.16 27.405 32.4 27.675 ;
     RECT  2.16 27.945 32.4 28.215 ;
     RECT  2.16 28.485 32.4 28.755 ;
     RECT  2.16 29.025 32.4 29.295 ;
     RECT  2.16 29.565 32.4 29.835 ;
     RECT  2.16 30.105 32.4 30.375 ;
     RECT  2.16 30.645 32.4 30.915 ;
     RECT  2.16 31.185 32.4 31.455 ;
     RECT  2.16 31.725 32.4 31.995 ;
     RECT  2.16 32.265 32.4 32.4 ;
    LAYER RVTP ;
     RECT  2.16 2.295 32.4 2.565 ;
     RECT  2.16 2.835 32.4 3.105 ;
     RECT  2.16 3.375 32.4 3.645 ;
     RECT  2.16 3.915 32.4 4.185 ;
     RECT  2.16 4.455 32.4 4.725 ;
     RECT  2.16 4.995 32.4 5.265 ;
     RECT  2.16 5.535 32.4 5.805 ;
     RECT  2.16 6.075 32.4 6.345 ;
     RECT  2.16 6.615 32.4 6.885 ;
     RECT  2.16 7.155 32.4 7.425 ;
     RECT  2.16 7.695 32.4 7.965 ;
     RECT  2.16 8.235 32.4 8.505 ;
     RECT  2.16 8.775 32.4 9.045 ;
     RECT  2.16 9.315 32.4 9.585 ;
     RECT  2.16 9.855 32.4 10.125 ;
     RECT  2.16 10.395 32.4 10.665 ;
     RECT  2.16 10.935 32.4 11.205 ;
     RECT  2.16 11.475 32.4 11.745 ;
     RECT  2.16 12.015 32.4 12.285 ;
     RECT  2.16 12.555 32.4 12.825 ;
     RECT  2.16 13.095 32.4 13.365 ;
     RECT  2.16 13.635 32.4 13.905 ;
     RECT  2.16 14.175 32.4 14.445 ;
     RECT  2.16 14.715 32.4 14.985 ;
     RECT  2.16 15.255 32.4 15.525 ;
     RECT  2.16 15.795 32.4 16.065 ;
     RECT  2.16 16.335 32.4 16.605 ;
     RECT  2.16 16.875 32.4 17.145 ;
     RECT  2.16 17.415 32.4 17.685 ;
     RECT  2.16 17.955 32.4 18.225 ;
     RECT  2.16 18.495 32.4 18.765 ;
     RECT  2.16 19.035 32.4 19.305 ;
     RECT  2.16 19.575 32.4 19.845 ;
     RECT  2.16 20.115 32.4 20.385 ;
     RECT  2.16 20.655 32.4 20.925 ;
     RECT  2.16 21.195 32.4 21.465 ;
     RECT  2.16 21.735 32.4 22.005 ;
     RECT  2.16 22.275 32.4 22.545 ;
     RECT  2.16 22.815 32.4 23.085 ;
     RECT  2.16 23.355 32.4 23.625 ;
     RECT  2.16 23.895 32.4 24.165 ;
     RECT  2.16 24.435 32.4 24.705 ;
     RECT  2.16 24.975 32.4 25.245 ;
     RECT  2.16 25.515 32.4 25.785 ;
     RECT  2.16 26.055 32.4 26.325 ;
     RECT  2.16 26.595 32.4 26.865 ;
     RECT  2.16 27.135 32.4 27.405 ;
     RECT  2.16 27.675 32.4 27.945 ;
     RECT  2.16 28.215 32.4 28.485 ;
     RECT  2.16 28.755 32.4 29.025 ;
     RECT  2.16 29.295 32.4 29.565 ;
     RECT  2.16 29.835 32.4 30.105 ;
     RECT  2.16 30.375 32.4 30.645 ;
     RECT  2.16 30.915 32.4 31.185 ;
     RECT  2.16 31.455 32.4 31.725 ;
     RECT  2.16 31.995 32.4 32.265 ;
    LAYER M1 ;
     RECT  2.16 2.151 32.4 32.409 ;
    LAYER M2 ;
     RECT  0.031 12.762 0.067 12.78 ;
     RECT  0.067 12.492 0.103 12.78 ;
     RECT  0.139 11.106 0.175 11.124 ;
     RECT  0.175 10.566 2.16 11.124 ;
     RECT  0.103 11.952 2.16 12.78 ;
     RECT  0.535 18.666 2.16 18.684 ;
     RECT  0.535 20.286 2.16 20.304 ;
     RECT  0.535 21.978 2.16 21.996 ;
     RECT  0.031 24.372 2.16 24.39 ;
     RECT  2.16 2.151 32.4 32.409 ;
     RECT  32.4 2.196 32.783 32.364 ;
     RECT  32.783 4.356 33.071 32.364 ;
     RECT  33.071 11.952 33.107 32.364 ;
     RECT  33.107 11.952 33.251 22.464 ;
     RECT  33.071 4.356 33.575 10.584 ;
     RECT  33.251 11.952 33.575 14.634 ;
     RECT  32.783 2.196 33.611 3.564 ;
     RECT  33.575 5.166 33.611 6.264 ;
     RECT  33.575 7.056 33.611 10.584 ;
     RECT  33.575 12.996 33.611 13.554 ;
     RECT  33.575 14.616 33.611 14.634 ;
     RECT  33.251 15.696 33.611 22.464 ;
     RECT  33.107 23.256 33.611 31.788 ;
     RECT  33.611 7.326 33.647 9.414 ;
     RECT  33.611 25.524 33.647 25.542 ;
     RECT  33.611 29.376 33.647 30.978 ;
     RECT  33.611 31.734 33.647 31.788 ;
     RECT  33.611 27.342 33.683 28.584 ;
     RECT  33.683 27.342 33.719 28.512 ;
     RECT  33.647 31.734 33.719 31.752 ;
     RECT  33.611 2.538 34.403 2.898 ;
     RECT  33.647 29.376 34.403 29.628 ;
     RECT  34.403 2.538 34.439 2.664 ;
     RECT  33.647 30.654 34.439 30.978 ;
     RECT  34.439 2.646 34.475 2.664 ;
     RECT  33.611 5.886 34.475 5.904 ;
     RECT  33.647 7.326 34.475 9.108 ;
     RECT  33.575 11.952 34.475 11.97 ;
     RECT  33.611 18.126 34.475 18.144 ;
     RECT  33.719 27.342 34.475 27.864 ;
     RECT  34.439 30.96 34.475 30.978 ;
     RECT  34.403 29.376 34.547 29.394 ;
    LAYER M3 ;
     RECT  32.256 0.091 32.274 0.331 ;
     RECT  34.452 0.523 34.47 0.763 ;
     RECT  34.416 0.763 34.47 0.955 ;
     RECT  0.108 0.811 0.126 1.099 ;
     RECT  0.036 1.099 0.126 1.133 ;
     RECT  34.38 0.955 34.47 1.195 ;
     RECT  33.012 1.387 33.03 1.627 ;
     RECT  31.608 0.331 32.274 1.819 ;
     RECT  33.012 1.627 33.606 1.819 ;
     RECT  31.608 1.819 33.606 2.219 ;
     RECT  29.415 2.143 29.505 2.227 ;
     RECT  31.608 2.219 33.57 2.227 ;
     RECT  29.415 2.227 30.114 2.251 ;
     RECT  28.908 2.251 30.114 2.263 ;
     RECT  31.248 2.227 33.57 2.263 ;
     RECT  2.415 2.143 2.505 2.413 ;
     RECT  7.815 2.143 7.905 2.413 ;
     RECT  13.215 2.143 13.305 2.413 ;
     RECT  18.615 2.143 18.705 2.413 ;
     RECT  24.015 2.143 24.105 2.413 ;
     RECT  0.036 1.133 0.054 2.443 ;
     RECT  25.668 2.461 25.686 2.569 ;
     RECT  28.908 2.263 33.57 2.569 ;
     RECT  0.036 2.443 0.162 2.573 ;
     RECT  34.344 1.195 34.47 2.597 ;
     RECT  24.015 2.413 24.297 2.641 ;
     RECT  25.668 2.569 26.406 2.641 ;
     RECT  28.692 2.569 33.57 2.641 ;
     RECT  34.38 2.597 34.47 2.669 ;
     RECT  23.976 2.641 26.406 2.759 ;
     RECT  27.648 2.641 33.57 2.803 ;
     RECT  34.38 2.669 34.398 2.903 ;
     RECT  23.976 2.759 24.39 2.909 ;
     RECT  25.308 2.759 26.406 3.029 ;
     RECT  27.54 2.803 33.57 3.307 ;
     RECT  27.468 3.307 33.57 3.355 ;
     RECT  27.468 3.355 33.606 3.407 ;
     RECT  27.468 3.407 32.778 3.437 ;
     RECT  0.036 2.573 0.09 4.075 ;
     RECT  25.308 3.029 26.046 4.081 ;
     RECT  27.612 3.437 32.778 4.109 ;
     RECT  33.588 3.407 33.606 4.219 ;
     RECT  25.308 4.081 26.19 4.261 ;
     RECT  33.552 4.219 33.606 4.651 ;
     RECT  25.308 4.261 26.334 4.657 ;
     RECT  25.308 4.657 26.802 4.757 ;
     RECT  25.308 4.757 26.19 4.765 ;
     RECT  24.015 2.909 24.39 5.035 ;
     RECT  25.2 4.765 26.19 5.035 ;
     RECT  33.012 4.651 33.606 5.275 ;
     RECT  24.015 5.035 26.19 5.611 ;
     RECT  27.612 4.109 32.202 5.707 ;
     RECT  32.976 5.275 33.606 5.707 ;
     RECT  0.036 4.075 0.126 5.755 ;
     RECT  27.612 5.707 33.606 5.881 ;
     RECT  34.452 4.843 34.47 5.909 ;
     RECT  24.015 5.611 26.334 5.995 ;
     RECT  23.796 5.995 26.334 6.007 ;
     RECT  27.576 5.881 33.606 6.143 ;
     RECT  23.796 6.007 26.802 6.313 ;
     RECT  23.58 6.313 26.802 6.379 ;
     RECT  27.576 6.143 32.058 6.379 ;
     RECT  23.58 6.379 32.058 6.539 ;
     RECT  23.58 6.539 32.022 6.809 ;
     RECT  23.652 6.809 32.022 6.953 ;
     RECT  23.652 6.953 28.422 7.223 ;
     RECT  33.048 6.143 33.606 7.799 ;
     RECT  29.232 6.953 32.022 8.005 ;
     RECT  29.232 8.005 32.094 8.159 ;
     RECT  23.904 7.223 28.422 8.203 ;
     RECT  33.048 7.799 33.066 8.231 ;
     RECT  23.616 8.203 28.422 8.275 ;
     RECT  29.232 8.159 32.058 8.275 ;
     RECT  23.616 8.275 32.058 8.779 ;
     RECT  0.036 5.755 0.162 9.019 ;
     RECT  34.452 7.321 34.47 9.197 ;
     RECT  23.472 8.779 32.058 9.355 ;
     RECT  33.588 8.731 33.606 9.391 ;
     RECT  33.588 9.391 33.642 9.437 ;
     RECT  33.588 9.437 33.606 9.595 ;
     RECT  23.364 9.355 32.094 10.049 ;
     RECT  21.888 10.471 21.906 10.561 ;
     RECT  33.048 9.595 33.606 10.589 ;
     RECT  21.348 10.561 21.906 10.741 ;
     RECT  20.268 7.387 20.286 10.769 ;
     RECT  21.348 10.741 22.518 10.831 ;
     RECT  23.364 10.049 32.058 10.831 ;
     RECT  0.036 9.019 0.198 10.859 ;
     RECT  0.036 10.859 0.162 11.129 ;
     RECT  33.048 10.589 33.066 11.563 ;
     RECT  21.348 10.831 32.094 11.785 ;
     RECT  21.168 11.785 32.094 11.821 ;
     RECT  21.132 11.821 32.094 11.911 ;
     RECT  21.06 11.911 32.094 11.975 ;
     RECT  34.452 11.947 34.47 12.029 ;
     RECT  33.048 11.563 33.606 12.361 ;
     RECT  32.94 12.361 33.606 12.461 ;
     RECT  21.06 11.975 32.058 12.523 ;
     RECT  0.036 11.129 0.126 12.749 ;
     RECT  0.036 12.749 0.054 12.785 ;
     RECT  14.868 12.757 14.886 12.857 ;
     RECT  20.484 12.523 32.058 13.055 ;
     RECT  33.048 12.461 33.606 13.469 ;
     RECT  20.484 13.055 31.986 13.801 ;
     RECT  19.944 13.801 32.058 13.901 ;
     RECT  2.415 2.413 2.697 13.963 ;
     RECT  13.215 2.413 13.497 13.963 ;
     RECT  2.304 13.963 2.697 14.009 ;
     RECT  13.104 13.963 13.497 14.009 ;
     RECT  20.052 13.901 32.058 14.135 ;
     RECT  20.448 14.135 32.058 14.549 ;
     RECT  33.552 13.469 33.606 14.587 ;
     RECT  33.228 14.587 33.606 14.639 ;
     RECT  33.228 14.639 33.246 14.779 ;
     RECT  33.048 14.779 33.246 15.211 ;
     RECT  20.52 14.549 32.058 15.295 ;
     RECT  20.448 15.295 32.058 15.331 ;
     RECT  20.448 15.331 32.274 15.449 ;
     RECT  2.415 14.009 2.697 15.592 ;
     RECT  13.215 14.009 13.497 15.592 ;
     RECT  2.304 15.592 2.697 15.629 ;
     RECT  13.104 15.592 13.497 15.629 ;
     RECT  33.012 15.211 33.246 15.643 ;
     RECT  20.448 15.449 32.058 15.691 ;
     RECT  20.16 15.691 32.058 15.791 ;
     RECT  33.012 15.643 33.606 15.827 ;
     RECT  20.268 15.791 32.058 16.061 ;
     RECT  33.228 15.827 33.606 16.097 ;
     RECT  20.736 16.061 32.058 16.529 ;
     RECT  33.3 16.097 33.606 16.879 ;
     RECT  20.736 16.529 32.022 17.185 ;
     RECT  33.084 16.879 33.606 17.213 ;
     RECT  2.415 15.629 2.697 17.275 ;
     RECT  13.215 15.629 13.497 17.311 ;
     RECT  2.304 17.275 2.697 17.339 ;
     RECT  13.104 17.311 13.497 17.357 ;
     RECT  20.664 17.185 32.022 17.681 ;
     RECT  21.744 17.681 32.022 17.995 ;
     RECT  33.552 17.213 33.606 18.031 ;
     RECT  21.744 17.995 32.094 18.149 ;
     RECT  34.452 18.121 34.47 18.269 ;
     RECT  33.048 18.031 33.606 18.761 ;
     RECT  0.54 18.661 0.558 18.941 ;
     RECT  33.084 18.761 33.606 18.941 ;
     RECT  21.96 18.149 32.094 18.959 ;
     RECT  33.156 18.941 33.606 19.133 ;
     RECT  21.96 18.959 32.022 19.337 ;
     RECT  32.004 19.337 32.022 19.499 ;
     RECT  21.96 19.337 31.266 19.768 ;
     RECT  21.672 19.768 31.266 19.805 ;
     RECT  32.04 20.011 32.058 20.111 ;
     RECT  33.588 19.133 33.606 20.203 ;
     RECT  33.012 20.203 33.606 20.417 ;
     RECT  21.96 19.805 31.266 20.461 ;
     RECT  18.615 2.413 18.897 20.539 ;
     RECT  0.54 20.281 0.558 20.573 ;
     RECT  18.615 20.539 18.954 20.579 ;
     RECT  20.664 17.681 20.682 20.587 ;
     RECT  21.96 20.461 31.95 20.965 ;
     RECT  20.484 20.587 20.682 21.101 ;
     RECT  21.96 20.965 32.094 21.271 ;
     RECT  21.96 21.271 32.202 21.541 ;
     RECT  33.048 20.417 33.606 21.541 ;
     RECT  21.96 21.541 33.606 21.659 ;
     RECT  30.456 21.659 33.606 21.725 ;
     RECT  20.664 21.101 20.682 21.937 ;
     RECT  20.664 21.937 20.79 21.965 ;
     RECT  30.456 21.725 32.058 22.001 ;
     RECT  0.54 21.973 0.558 22.253 ;
     RECT  33.156 21.725 33.606 22.469 ;
     RECT  21.96 21.659 29.697 22.621 ;
     RECT  30.456 22.001 31.878 22.621 ;
     RECT  33.156 22.469 33.174 22.711 ;
     RECT  33.084 22.711 33.174 22.987 ;
     RECT  21.96 22.621 31.878 23.081 ;
     RECT  14.796 22.987 14.814 23.117 ;
     RECT  30.672 23.081 31.878 23.125 ;
     RECT  33.048 22.987 33.174 23.227 ;
     RECT  21.96 23.081 29.754 23.357 ;
     RECT  30.672 23.125 32.022 23.521 ;
     RECT  11.556 23.083 11.574 23.549 ;
     RECT  7.815 2.413 8.097 23.593 ;
     RECT  33.048 23.227 33.606 23.693 ;
     RECT  11.376 23.665 11.394 23.885 ;
     RECT  30.672 23.521 32.058 23.971 ;
     RECT  30.492 23.971 32.058 24.089 ;
     RECT  21.96 23.357 29.697 24.241 ;
     RECT  30.492 24.089 31.302 24.241 ;
     RECT  21.96 24.241 31.302 24.317 ;
     RECT  10.224 18.157 10.242 24.359 ;
     RECT  33.084 23.693 33.606 24.523 ;
     RECT  33.012 24.523 33.606 24.749 ;
     RECT  25.236 24.317 31.302 24.871 ;
     RECT  32.04 24.089 32.058 24.871 ;
     RECT  25.236 24.871 32.058 24.899 ;
     RECT  21.96 24.317 24.498 25.051 ;
     RECT  25.236 24.899 25.362 25.051 ;
     RECT  11.736 24.907 11.754 25.169 ;
     RECT  21.96 25.051 25.362 25.169 ;
     RECT  26.136 24.899 26.226 25.277 ;
     RECT  27.036 24.899 32.058 25.321 ;
     RECT  27.036 25.321 32.526 25.349 ;
     RECT  21.96 25.169 25.326 25.439 ;
     RECT  27.288 25.349 32.526 25.439 ;
     RECT  21.96 25.439 24.354 25.475 ;
     RECT  11.52 25.285 11.538 25.517 ;
     RECT  33.588 24.749 33.606 25.519 ;
     RECT  27.828 25.439 32.526 25.745 ;
     RECT  28.044 25.745 32.526 25.853 ;
     RECT  28.152 25.853 32.058 26.321 ;
     RECT  28.152 26.321 31.842 26.393 ;
     RECT  28.224 26.393 31.842 26.555 ;
     RECT  18.615 20.579 18.897 26.635 ;
     RECT  21.96 25.475 24.297 26.671 ;
     RECT  33.588 25.519 33.642 26.671 ;
     RECT  33.048 26.671 33.642 26.717 ;
     RECT  18.615 26.635 18.954 26.789 ;
     RECT  11.268 26.905 11.286 27.149 ;
     RECT  33.588 26.717 33.642 27.149 ;
     RECT  28.332 26.555 31.842 27.301 ;
     RECT  21.96 26.671 24.39 27.329 ;
     RECT  28.332 27.301 31.914 27.355 ;
     RECT  28.008 27.355 31.914 27.409 ;
     RECT  28.008 27.409 32.058 27.599 ;
     RECT  29.16 27.599 32.058 27.779 ;
     RECT  28.008 27.599 28.386 27.869 ;
     RECT  28.368 27.869 28.386 27.917 ;
     RECT  34.452 27.337 34.47 28.013 ;
     RECT  29.196 27.779 32.058 28.021 ;
     RECT  29.196 28.021 32.274 28.139 ;
     RECT  33.588 27.149 33.606 28.291 ;
     RECT  33.048 28.291 33.606 28.381 ;
     RECT  25.308 25.439 25.326 28.409 ;
     RECT  13.215 17.357 13.497 28.417 ;
     RECT  33.048 28.381 33.642 28.489 ;
     RECT  12.528 28.417 13.497 28.679 ;
     RECT  12.348 28.789 12.366 28.829 ;
     RECT  29.196 28.139 32.13 29.219 ;
     RECT  33.048 28.489 33.714 29.501 ;
     RECT  33.084 29.501 33.714 29.605 ;
     RECT  34.524 29.371 34.542 29.605 ;
     RECT  33.084 29.605 34.542 29.741 ;
     RECT  29.232 29.219 32.13 30.181 ;
     RECT  0.036 24.367 0.054 30.235 ;
     RECT  26.208 25.277 26.226 30.235 ;
     RECT  0.036 30.235 0.126 30.269 ;
     RECT  29.232 30.181 32.274 30.379 ;
     RECT  26.208 30.235 26.658 30.451 ;
     RECT  0.108 30.269 0.126 30.461 ;
     RECT  26.208 30.451 26.838 30.577 ;
     RECT  26.208 30.577 27.486 30.613 ;
     RECT  26.208 30.613 27.63 30.721 ;
     RECT  28.908 30.379 32.274 30.721 ;
     RECT  26.208 30.721 32.274 30.983 ;
     RECT  33.588 29.741 34.542 30.991 ;
     RECT  28.26 30.983 32.274 31.229 ;
     RECT  21.96 27.329 24.297 31.379 ;
     RECT  33.084 30.991 34.542 31.459 ;
     RECT  22.068 31.379 24.297 31.729 ;
     RECT  25.164 31.531 25.182 31.729 ;
     RECT  2.415 17.339 2.697 31.765 ;
     RECT  22.068 31.729 25.182 31.765 ;
     RECT  26.208 30.983 27.522 31.765 ;
     RECT  5.472 31.729 5.49 31.801 ;
     RECT  20.772 21.965 20.79 31.829 ;
     RECT  7.56 23.593 8.097 31.891 ;
     RECT  22.068 31.765 27.522 31.915 ;
     RECT  28.26 31.229 32.166 31.915 ;
     RECT  3.528 31.729 3.546 31.919 ;
     RECT  4.392 31.801 4.41 31.919 ;
     RECT  5.184 31.801 5.49 31.919 ;
     RECT  6.84 31.891 8.097 31.919 ;
     RECT  22.068 31.915 32.166 31.919 ;
     RECT  28.152 31.919 32.166 31.955 ;
     RECT  6.84 31.919 6.858 31.991 ;
     RECT  22.068 31.919 25.65 31.991 ;
     RECT  28.152 31.955 30.402 31.991 ;
     RECT  4.248 31.927 4.266 31.997 ;
     RECT  5.328 31.919 5.346 31.997 ;
     RECT  2.34 31.765 2.697 32.035 ;
     RECT  22.068 31.991 24.297 32.063 ;
     RECT  25.488 31.991 25.65 32.063 ;
     RECT  31.284 31.955 32.166 32.071 ;
     RECT  2.304 32.035 2.697 32.147 ;
     RECT  7.815 31.919 8.097 32.147 ;
     RECT  13.215 28.679 13.497 32.147 ;
     RECT  18.615 26.789 18.897 32.147 ;
     RECT  24.012 32.063 24.297 32.147 ;
     RECT  23.004 32.063 23.202 32.189 ;
     RECT  28.224 31.991 30.15 32.225 ;
     RECT  23.004 32.189 23.022 32.261 ;
     RECT  24.012 32.147 24.105 32.261 ;
     RECT  25.488 32.063 25.506 32.261 ;
     RECT  27.36 31.919 27.378 32.261 ;
     RECT  28.224 32.225 28.494 32.261 ;
     RECT  29.232 32.225 30.078 32.261 ;
     RECT  31.284 32.071 32.274 32.333 ;
     RECT  28.224 32.261 28.242 32.369 ;
     RECT  29.232 32.261 29.505 32.369 ;
     RECT  2.304 32.147 2.505 32.417 ;
     RECT  7.815 32.147 7.905 32.417 ;
     RECT  13.215 32.147 13.305 32.417 ;
     RECT  18.615 32.147 18.705 32.417 ;
     RECT  24.015 32.261 24.105 32.417 ;
     RECT  29.415 32.369 29.505 32.417 ;
     RECT  33.048 31.459 34.542 32.765 ;
     RECT  33.084 32.765 34.542 32.957 ;
     RECT  33.624 32.957 34.542 33.197 ;
     RECT  33.696 33.197 34.542 33.533 ;
     RECT  33.696 33.533 34.47 33.629 ;
     RECT  2.304 32.417 2.322 33.773 ;
     RECT  31.752 32.333 32.274 33.821 ;
     RECT  33.696 33.629 34.29 34.061 ;
     RECT  33.696 34.061 33.714 34.253 ;
     RECT  32.256 33.821 32.274 34.493 ;
    LAYER M4 ;
     RECT  0.025 1.104 0.06 1.128 ;
     RECT  0.025 30.24 0.06 30.264 ;
     RECT  2.408 2.148 2.512 32.412 ;
     RECT  2.512 2.418 2.704 32.142 ;
     RECT  2.704 7.392 7.808 7.416 ;
     RECT  2.704 13.968 7.808 13.992 ;
     RECT  2.704 15.6 7.808 15.624 ;
     RECT  2.704 17.328 7.808 17.352 ;
     RECT  2.704 23.856 7.808 23.88 ;
     RECT  2.704 25.488 7.808 25.512 ;
     RECT  2.704 27.12 7.808 27.144 ;
     RECT  2.704 28.8 7.808 28.824 ;
     RECT  4.237 31.968 7.808 31.992 ;
     RECT  7.808 2.148 7.912 32.412 ;
     RECT  7.912 2.418 8.104 32.142 ;
     RECT  8.629 0.048 8.713 0.072 ;
     RECT  8.104 27.12 11.297 27.144 ;
     RECT  8.104 23.856 11.405 23.88 ;
     RECT  8.104 25.488 11.549 25.512 ;
     RECT  8.104 7.392 13.208 7.416 ;
     RECT  8.104 13.968 13.208 13.992 ;
     RECT  8.104 15.6 13.208 17.352 ;
     RECT  11.545 23.088 13.208 23.112 ;
     RECT  8.104 28.8 13.208 28.824 ;
     RECT  8.104 31.968 13.208 31.992 ;
     RECT  13.208 2.148 13.312 32.412 ;
     RECT  13.312 2.418 13.504 32.142 ;
     RECT  13.504 23.088 14.785 23.112 ;
     RECT  14.785 22.992 14.825 23.112 ;
     RECT  13.504 7.392 18.608 7.416 ;
     RECT  13.504 13.968 18.608 13.992 ;
     RECT  13.504 15.6 18.608 17.352 ;
     RECT  14.825 22.992 18.608 23.016 ;
     RECT  13.504 31.968 18.608 31.992 ;
     RECT  18.608 2.148 18.712 32.412 ;
     RECT  18.712 2.418 18.904 32.142 ;
     RECT  18.904 19.92 19.379 20.568 ;
     RECT  18.904 7.392 20.297 7.416 ;
     RECT  19.379 19.92 20.473 19.944 ;
     RECT  20.473 19.92 20.557 21.096 ;
     RECT  18.904 15.6 21.409 17.352 ;
     RECT  20.557 19.92 21.661 20.616 ;
     RECT  18.904 13.968 21.733 13.992 ;
     RECT  21.409 15.504 21.733 17.352 ;
     RECT  18.904 31.968 22.097 31.992 ;
     RECT  21.373 12 22.565 12.024 ;
     RECT  18.904 22.992 22.637 23.016 ;
     RECT  21.733 13.968 22.849 17.352 ;
     RECT  22.849 13.968 22.853 17.64 ;
     RECT  22.853 14.688 23.033 17.64 ;
     RECT  23.677 6.672 23.785 6.696 ;
     RECT  23.785 6 24.001 6.696 ;
     RECT  23.965 2.88 24.008 2.904 ;
     RECT  24.001 6 24.008 7.656 ;
     RECT  23.033 14.688 24.008 17.4 ;
     RECT  21.661 19.776 24.008 20.616 ;
     RECT  22.201 32.016 24.008 32.04 ;
     RECT  24.008 2.148 24.112 32.412 ;
     RECT  24.112 2.418 24.304 32.142 ;
     RECT  24.304 4.8 24.419 7.8 ;
     RECT  24.304 16.272 24.419 21.24 ;
     RECT  24.304 25.44 24.419 25.464 ;
     RECT  24.304 27.072 24.419 27.096 ;
     RECT  24.419 4.8 24.689 5.112 ;
     RECT  24.304 2.688 24.707 3.24 ;
     RECT  24.304 9.072 24.803 12.36 ;
     RECT  24.803 9.072 24.844 11.976 ;
     RECT  24.304 24.288 24.995 24.312 ;
     RECT  24.304 31.92 24.995 31.944 ;
     RECT  24.844 9.072 25.049 10.488 ;
     RECT  24.844 11.952 25.057 11.976 ;
     RECT  24.304 23.136 25.121 23.16 ;
     RECT  24.419 16.272 25.157 21 ;
     RECT  24.707 2.688 25.235 3.144 ;
     RECT  24.689 4.8 25.235 4.824 ;
     RECT  25.049 9.648 25.445 10.488 ;
     RECT  24.304 13.968 25.525 15.192 ;
     RECT  25.157 16.272 25.525 19.992 ;
     RECT  25.525 13.968 25.553 19.992 ;
     RECT  25.553 13.968 25.571 19.944 ;
     RECT  25.441 21.12 25.669 21.144 ;
     RECT  24.419 7.776 25.801 7.8 ;
     RECT  25.657 13.2 25.837 13.368 ;
     RECT  24.419 6.624 25.873 6.696 ;
     RECT  25.801 7.776 25.873 7.896 ;
     RECT  25.873 6.624 25.909 7.896 ;
     RECT  25.837 13.104 25.909 13.368 ;
     RECT  25.235 2.832 25.913 3.144 ;
     RECT  25.445 10.32 25.957 10.488 ;
     RECT  25.909 12.24 26.003 13.368 ;
     RECT  25.909 6.624 26.108 8.472 ;
     RECT  26.003 12.528 26.147 13.368 ;
     RECT  26.108 6.192 26.195 8.472 ;
     RECT  26.108 22.704 26.195 22.728 ;
     RECT  26.195 6.672 26.243 7.56 ;
     RECT  26.147 12.528 26.273 12.888 ;
     RECT  25.913 2.832 26.291 2.856 ;
     RECT  26.088 24.096 26.309 24.12 ;
     RECT  25.669 21.12 26.341 21.72 ;
     RECT  25.571 14.496 26.345 19.944 ;
     RECT  26.243 6.816 26.381 7.56 ;
     RECT  26.341 20.976 26.428 22.152 ;
     RECT  26.345 14.496 26.435 18.792 ;
     RECT  25.957 10.32 26.521 11.016 ;
     RECT  26.273 12.528 26.669 12.552 ;
     RECT  26.341 30.24 26.669 30.264 ;
     RECT  26.345 19.824 26.725 19.944 ;
     RECT  26.521 10.32 27.02 11.16 ;
     RECT  26.428 20.976 27.029 21.72 ;
     RECT  26.435 14.496 27.061 18.264 ;
     RECT  26.725 19.824 27.061 19.992 ;
     RECT  27.02 10.32 27.107 11.304 ;
     RECT  27.02 12.336 27.107 12.36 ;
     RECT  27.107 10.32 27.241 11.16 ;
     RECT  27.133 24.24 27.277 24.264 ;
     RECT  26.381 7.296 27.425 7.56 ;
     RECT  27.425 7.296 27.493 7.416 ;
     RECT  27.013 3.408 27.497 3.432 ;
     RECT  27.493 6.384 27.497 7.416 ;
     RECT  27.277 24.24 27.589 25.128 ;
     RECT  27.241 10.032 27.596 11.16 ;
     RECT  27.061 14.064 27.596 18.264 ;
     RECT  27.497 6.384 27.637 7.32 ;
     RECT  27.596 9.504 27.637 11.16 ;
     RECT  27.596 13.632 27.637 18.264 ;
     RECT  27.637 13.008 27.641 18.264 ;
     RECT  27.641 18.24 27.677 18.264 ;
     RECT  27.596 2.688 27.683 2.856 ;
     RECT  27.637 8.544 27.779 11.16 ;
     RECT  27.829 18.624 27.853 18.648 ;
     RECT  27.683 2.832 27.865 2.856 ;
     RECT  27.853 18.624 27.916 18.792 ;
     RECT  27.637 5.712 27.929 7.32 ;
     RECT  27.916 18.768 27.937 18.792 ;
     RECT  27.061 19.824 27.971 20.04 ;
     RECT  27.877 23.184 28.001 23.208 ;
     RECT  27.929 5.712 28.028 7.08 ;
     RECT  27.971 19.968 28.028 20.04 ;
     RECT  27.029 21.264 28.028 21.72 ;
     RECT  27.877 27.36 28.037 27.384 ;
     RECT  27.589 24.24 28.069 25.416 ;
     RECT  27.997 4.512 28.115 4.536 ;
     RECT  28.028 5.616 28.115 7.08 ;
     RECT  28.028 19.968 28.115 21.72 ;
     RECT  27.641 13.008 28.259 16.968 ;
     RECT  28.141 31.92 28.259 31.944 ;
     RECT  28.069 24.24 28.281 25.944 ;
     RECT  28.259 13.008 28.325 13.272 ;
     RECT  28.316 27.888 28.403 27.912 ;
     RECT  28.285 30.816 28.403 30.84 ;
     RECT  28.281 24.24 28.537 25.128 ;
     RECT  27.779 8.832 28.573 11.16 ;
     RECT  28.573 8.832 28.645 11.4 ;
     RECT  28.115 21.648 28.789 21.72 ;
     RECT  28.645 8.832 28.796 11.976 ;
     RECT  28.796 8.304 28.837 11.976 ;
     RECT  28.681 2.592 28.892 2.616 ;
     RECT  28.259 14.496 28.892 16.968 ;
     RECT  28.892 14.496 28.933 17.832 ;
     RECT  28.933 14.496 29.077 18.792 ;
     RECT  28.789 21.648 29.077 22.152 ;
     RECT  29.077 14.496 29.105 18.936 ;
     RECT  28.115 19.968 29.105 20.04 ;
     RECT  29.077 21.648 29.221 22.488 ;
     RECT  28.537 23.52 29.221 25.128 ;
     RECT  28.885 3.936 29.249 3.96 ;
     RECT  28.645 5.184 29.249 5.208 ;
     RECT  29.105 14.496 29.249 20.04 ;
     RECT  29.221 21.648 29.257 25.128 ;
     RECT  29.221 26.256 29.257 26.28 ;
     RECT  28.892 2.256 29.408 2.616 ;
     RECT  29.249 3.936 29.408 5.208 ;
     RECT  28.115 6.192 29.408 6.84 ;
     RECT  28.837 8.304 29.408 12.744 ;
     RECT  29.249 14.496 29.408 20.568 ;
     RECT  29.257 21.648 29.408 26.28 ;
     RECT  29.005 32.16 29.408 32.184 ;
     RECT  29.408 2.148 29.512 32.412 ;
     RECT  29.512 2.418 29.704 32.142 ;
     RECT  29.704 23.328 29.765 23.352 ;
     RECT  29.704 9.36 29.843 9.384 ;
     RECT  29.704 12.48 29.843 14.136 ;
     RECT  29.704 18.24 29.843 18.264 ;
     RECT  29.843 13.296 29.909 14.136 ;
     RECT  29.704 11.136 30.017 11.16 ;
     RECT  29.704 27.84 30.593 27.864 ;
     RECT  29.704 2.832 30.809 3.96 ;
     RECT  29.704 31.152 30.845 31.848 ;
     RECT  30.809 2.832 30.953 3.816 ;
     RECT  30.845 31.152 30.953 31.56 ;
     RECT  30.953 31.536 32.033 31.56 ;
     RECT  30.953 3.792 32.065 3.816 ;
     RECT  31.597 0.336 32.245 0.36 ;
     RECT  31.741 33.792 32.245 33.816 ;
     RECT  32.461 1.824 32.749 1.848 ;
     RECT  32.749 1.824 32.965 2.52 ;
     RECT  32.065 3.552 32.965 3.816 ;
     RECT  32.461 5.712 32.965 5.736 ;
     RECT  32.965 1.824 33.001 3.816 ;
     RECT  32.965 5.28 33.001 5.736 ;
     RECT  33.001 1.392 33.037 5.736 ;
     RECT  31.525 11.328 33.037 11.352 ;
     RECT  32.929 12.432 33.037 12.456 ;
     RECT  33.001 15.216 33.037 15.48 ;
     RECT  33.001 20.208 33.037 20.232 ;
     RECT  32.497 21.696 33.037 21.72 ;
     RECT  33.001 24.528 33.037 24.552 ;
     RECT  32.497 25.824 33.037 25.848 ;
     RECT  31.489 26.88 33.037 26.904 ;
     RECT  32.137 32.496 33.037 32.52 ;
     RECT  33.037 18.048 33.073 18.696 ;
     RECT  33.037 22.992 33.073 24.552 ;
     RECT  33.037 29.472 33.073 29.496 ;
     RECT  32.245 31.2 33.073 31.224 ;
     RECT  33.037 32.496 33.073 32.76 ;
     RECT  32.245 33.792 33.073 34.488 ;
     RECT  33.073 17.184 33.145 18.936 ;
     RECT  33.037 20.208 33.145 21.72 ;
     RECT  33.073 22.8 33.145 24.744 ;
     RECT  33.037 14.784 33.217 15.48 ;
     RECT  33.217 14.592 33.289 15.912 ;
     RECT  33.037 9.6 33.541 13.32 ;
     RECT  33.289 14.592 33.541 16.104 ;
     RECT  33.145 17.184 33.541 19.128 ;
     RECT  33.037 28.416 33.541 28.44 ;
     RECT  33.073 29.472 33.541 29.736 ;
     RECT  33.037 1.392 33.577 7.896 ;
     RECT  33.541 9.6 33.577 19.128 ;
     RECT  33.145 20.208 33.577 24.744 ;
     RECT  33.037 25.824 33.577 26.904 ;
     RECT  33.541 28.416 33.577 29.736 ;
     RECT  33.073 31.008 33.577 34.488 ;
     RECT  32.245 0.096 34.333 0.36 ;
     RECT  33.577 1.392 34.333 34.488 ;
     RECT  34.333 0.096 34.524 34.488 ;
     RECT  34.524 33.504 34.553 33.528 ;
    LAYER M5 ;
     RECT  8.64 0.037 8.664 2.137 ;
     RECT  2.4 2.137 2.52 2.151 ;
     RECT  13.2 2.137 13.32 2.151 ;
     RECT  18.6 2.137 18.72 2.151 ;
     RECT  24 2.137 24.12 2.151 ;
     RECT  29.4 2.137 29.52 2.151 ;
     RECT  29.4 2.151 29.712 2.245 ;
     RECT  28.944 2.245 29.712 2.581 ;
     RECT  24 2.151 24.312 2.677 ;
     RECT  24 2.677 25.944 2.821 ;
     RECT  27.648 2.677 27.672 2.821 ;
     RECT  28.752 2.581 29.712 2.821 ;
     RECT  24 2.821 26.28 3.397 ;
     RECT  27.648 2.821 29.712 3.397 ;
     RECT  24 3.397 29.712 7.811 ;
     RECT  26.112 7.811 29.712 9.349 ;
     RECT  26.112 9.349 29.832 10.981 ;
     RECT  24 7.811 24.696 11.269 ;
     RECT  24 11.269 24.792 11.941 ;
     RECT  25.968 10.981 29.832 11.941 ;
     RECT  7.8 2.137 8.664 16.547 ;
     RECT  24 11.941 29.832 18.275 ;
     RECT  18.6 2.151 18.912 19.909 ;
     RECT  24 18.275 29.712 20.003 ;
     RECT  18.6 19.909 19.368 20.579 ;
     RECT  24 20.003 26.28 20.965 ;
     RECT  27.648 20.003 29.712 21.637 ;
     RECT  24 20.965 26.376 21.731 ;
     RECT  24 21.731 25.08 23.171 ;
     RECT  26.16 21.731 26.376 24.131 ;
     RECT  27.6 21.637 29.712 25.139 ;
     RECT  27.6 25.139 28.248 25.427 ;
     RECT  29.232 25.139 29.712 26.291 ;
     RECT  27.888 25.427 28.248 27.395 ;
     RECT  28.224 27.395 28.248 27.877 ;
     RECT  26.352 24.131 26.376 30.275 ;
     RECT  28.224 27.877 28.392 30.851 ;
     RECT  24 23.171 24.984 31.955 ;
     RECT  28.224 30.851 28.248 31.955 ;
     RECT  20.496 21.061 20.52 32.003 ;
     RECT  2.4 2.151 2.712 32.409 ;
     RECT  7.8 16.547 8.112 32.409 ;
     RECT  13.2 2.151 13.512 32.409 ;
     RECT  18.6 20.579 18.912 32.409 ;
     RECT  24 31.955 24.312 32.409 ;
     RECT  29.4 26.291 29.712 32.409 ;
     RECT  2.4 32.409 2.52 32.423 ;
     RECT  7.8 32.409 7.92 32.423 ;
     RECT  13.2 32.409 13.32 32.423 ;
     RECT  18.6 32.409 18.72 32.423 ;
     RECT  24 32.409 24.12 32.423 ;
     RECT  29.4 32.409 29.52 32.423 ;
     RECT  27.672 2.677 28.752 2.821 ;
     RECT  26.28 2.821 27.648 3.397 ;
     RECT  24.696 7.811 26.112 10.981 ;
     RECT  24.696 10.981 25.968 11.269 ;
     RECT  24.792 11.269 25.968 11.941 ;
     RECT  26.28 20.003 27.648 20.965 ;
     RECT  26.376 20.965 27.648 21.637 ;
     RECT  26.376 21.637 27.6 25.427 ;
     RECT  25.08 21.731 26.16 23.171 ;
     RECT  24.984 23.171 26.16 24.131 ;
     RECT  24.984 24.131 26.352 30.275 ;
     RECT  28.248 25.139 29.232 26.291 ;
     RECT  26.376 25.427 27.888 27.395 ;
     RECT  28.248 26.291 29.4 27.877 ;
     RECT  28.392 27.877 29.4 30.851 ;
     RECT  28.248 30.851 29.4 31.955 ;
  END
END ot_hgi_qw_ovmeta
END LIBRARY
